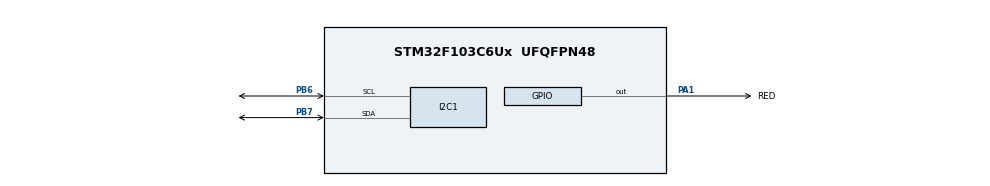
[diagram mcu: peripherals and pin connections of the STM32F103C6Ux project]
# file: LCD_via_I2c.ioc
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Mcu.Family=STM32F1
Mcu.Name=STM32F103C6Ux
Mcu.Package=UFQFPN48
NVIC.PriorityGroup=NVIC_PRIORITYGROUP_4
NVIC.TIM2_IRQn=true\:0\:0\:false\:false\:true\:true\:true\:true
PA1.GPIO_Label=RED
PA1.Signal=GPIO_Output
PA13.Mode=Serial_Wire
PA13.Signal=SYS_JTMS-SWDIO
PA14.Mode=Serial_Wire
PA14.Signal=SYS_JTCK-SWCLK
PB6.Mode=I2C
PB6.Signal=I2C1_SCL
PB7.Mode=I2C
PB7.Signal=I2C1_SDA
ProjectManager.HeapSize=0x200
ProjectManager.StackSize=0x400
ProjectManager.TargetToolchain=STM32CubeIDE
RCC.AHBFreq_Value=8000000
RCC.APB1CLKDivider=RCC_HCLK_DIV2
RCC.APB1Freq_Value=4000000
RCC.APB1TimFreq_Value=8000000
RCC.APB2Freq_Value=8000000
RCC.APB2TimFreq_Value=8000000
RCC.HCLKFreq_Value=8000000
RCC.PLLMUL=RCC_PLL_MUL9
RCC.SYSCLKFreq_VALUE=8000000
RCC.USBFreq_Value=36000000
TIM2.Period=9
TIM2.Prescaler=7999
VP_TIM2_VS_ClockSourceINT.Mode=Internal
board=custom

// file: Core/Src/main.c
/* USER CODE BEGIN Header */
/**
  ******************************************************************************
  * @file           : main.c
  * @brief          : Main program body
  ******************************************************************************
  * @attention
  *
  * Copyright (c) 2022 STMicroelectronics.
  * All rights reserved.
  *
  * This software is licensed under terms that can be found in the LICENSE file
  * in the root directory of this software component.
  * If no LICENSE file comes with this software, it is provided AS-IS.
  *
  ******************************************************************************
  */
/* USER CODE END Header */
#include "main.h"

/* USER CODE BEGIN Includes */
#include "software_timer.h"
#include "i2c-lcd-v2.h"
#include "liquidcrystal_i2c.h"
#include "CLCD_i2c.h"
#include "app_i2c_lcd.h"
/* USER CODE END Includes */

I2C_HandleTypeDef hi2c1;

TIM_HandleTypeDef htim2;

/* USER CODE BEGIN PV */
CLCD_I2C_Name LCD1;
/* USER CODE END PV */

void SystemClock_Config(void);
static void MX_GPIO_Init(void);
static void MX_I2C1_Init(void);
static void MX_TIM2_Init(void);

int main(void)
{

  /* MCU Configuration--------------------------------------------------------*/

  /* Reset of all peripherals, Initializes the Flash interface and the Systick. */
  HAL_Init();

  /* Configure the system clock */
  SystemClock_Config();

  /* Initialize all configured peripherals */
  MX_GPIO_Init();
  MX_I2C1_Init();
  MX_TIM2_Init();
  /* USER CODE BEGIN 2 */
  HAL_TIM_Base_Start_IT(&htim2);

  	  // CLCD_i2c
//  CLCD_I2C_Init(&LCD1, &hi2c1, 0x4E, 16, 2);
//  CLCD_I2C_SetCursor(&LCD1, 0, 0);
//  CLCD_I2C_WriteString(&LCD1, "Hello World");
//  CLCD_I2C_SetCursor(&LCD1, 0, 1);
//  CLCD_I2C_WriteString(&LCD1, "From BK");

  	  //i2c-lcd-v2
  HAL_Delay(1000);
  lcd_init();
  lcd_goto_XY(1,0);
  lcd_send_string("Hello World");
  HAL_Delay(50);
  lcd_goto_XY(2,0);
  lcd_send_string("From BK");

  	  // app_i2c_lcd
//  	HAL_Delay(1000);
//  	Lcd_Initialization();
//  	Lcd_Goto_XY(0,0);
//  	Lcd_Send_String("Hello World");
//  	HAL_Delay(50);
  /* USER CODE END 2 */

  /* Infinite loop */
  /* USER CODE BEGIN WHILE */
  setTimer1(100);
  while (1)
  {
    /* USER CODE END WHILE */

    /* USER CODE BEGIN 3 */
	  if (timer1_flag == 1){
		  HAL_GPIO_TogglePin(RED_GPIO_Port, RED_Pin);
		  setTimer1(100);
	  }
  }
  /* USER CODE END 3 */
}

void SystemClock_Config(void)
{
  RCC_OscInitTypeDef RCC_OscInitStruct = {0};
  RCC_ClkInitTypeDef RCC_ClkInitStruct = {0};

  /** Initializes the RCC Oscillators according to the specified parameters
  * in the RCC_OscInitTypeDef structure.
  */
  RCC_OscInitStruct.OscillatorType = RCC_OSCILLATORTYPE_HSI;
  RCC_OscInitStruct.HSIState = RCC_HSI_ON;
  RCC_OscInitStruct.HSICalibrationValue = RCC_HSICALIBRATION_DEFAULT;
  RCC_OscInitStruct.PLL.PLLState = RCC_PLL_NONE;
  if (HAL_RCC_OscConfig(&RCC_OscInitStruct) != HAL_OK)
  {
    Error_Handler();
  }

  /** Initializes the CPU, AHB and APB buses clocks
  */
  RCC_ClkInitStruct.ClockType = RCC_CLOCKTYPE_HCLK|RCC_CLOCKTYPE_SYSCLK
                              |RCC_CLOCKTYPE_PCLK1|RCC_CLOCKTYPE_PCLK2;
  RCC_ClkInitStruct.SYSCLKSource = RCC_SYSCLKSOURCE_HSI;
  RCC_ClkInitStruct.AHBCLKDivider = RCC_SYSCLK_DIV1;
  RCC_ClkInitStruct.APB1CLKDivider = RCC_HCLK_DIV1;
  RCC_ClkInitStruct.APB2CLKDivider = RCC_HCLK_DIV1;

  if (HAL_RCC_ClockConfig(&RCC_ClkInitStruct, FLASH_LATENCY_0) != HAL_OK)
  {
    Error_Handler();
  }
}

static void MX_I2C1_Init(void)
{

  hi2c1.Instance = I2C1;
  hi2c1.Init.ClockSpeed = 100000;
  hi2c1.Init.DutyCycle = I2C_DUTYCYCLE_2;
  hi2c1.Init.OwnAddress1 = 0;
  hi2c1.Init.AddressingMode = I2C_ADDRESSINGMODE_7BIT;
  hi2c1.Init.DualAddressMode = I2C_DUALADDRESS_DISABLE;
  hi2c1.Init.OwnAddress2 = 0;
  hi2c1.Init.GeneralCallMode = I2C_GENERALCALL_DISABLE;
  hi2c1.Init.NoStretchMode = I2C_NOSTRETCH_DISABLE;
  if (HAL_I2C_Init(&hi2c1) != HAL_OK)
  {
    Error_Handler();
  }

}

static void MX_TIM2_Init(void)
{

  TIM_ClockConfigTypeDef sClockSourceConfig = {0};
  TIM_MasterConfigTypeDef sMasterConfig = {0};

  htim2.Instance = TIM2;
  htim2.Init.Prescaler = 7999;
  htim2.Init.CounterMode = TIM_COUNTERMODE_UP;
  htim2.Init.Period = 9;
  htim2.Init.ClockDivision = TIM_CLOCKDIVISION_DIV1;
  htim2.Init.AutoReloadPreload = TIM_AUTORELOAD_PRELOAD_DISABLE;
  if (HAL_TIM_Base_Init(&htim2) != HAL_OK)
  {
    Error_Handler();
  }
  sClockSourceConfig.ClockSource = TIM_CLOCKSOURCE_INTERNAL;
  if (HAL_TIM_ConfigClockSource(&htim2, &sClockSourceConfig) != HAL_OK)
  {
    Error_Handler();
  }
  sMasterConfig.MasterOutputTrigger = TIM_TRGO_RESET;
  sMasterConfig.MasterSlaveMode = TIM_MASTERSLAVEMODE_DISABLE;
  if (HAL_TIMEx_MasterConfigSynchronization(&htim2, &sMasterConfig) != HAL_OK)
  {
    Error_Handler();
  }

}

static void MX_GPIO_Init(void)
{
  GPIO_InitTypeDef GPIO_InitStruct = {0};

  /* GPIO Ports Clock Enable */
  __HAL_RCC_GPIOA_CLK_ENABLE();
  __HAL_RCC_GPIOB_CLK_ENABLE();

  /*Configure GPIO pin Output Level */
  HAL_GPIO_WritePin(RED_GPIO_Port, RED_Pin, GPIO_PIN_RESET);

  /*Configure GPIO pin : RED_Pin */
  GPIO_InitStruct.Pin = RED_Pin;
  GPIO_InitStruct.Mode = GPIO_MODE_OUTPUT_PP;
  GPIO_InitStruct.Pull = GPIO_NOPULL;
  GPIO_InitStruct.Speed = GPIO_SPEED_FREQ_LOW;
  HAL_GPIO_Init(RED_GPIO_Port, &GPIO_InitStruct);

}

/* USER CODE BEGIN 4 */
void HAL_TIM_PeriodElapsedCallback ( TIM_HandleTypeDef * htim )
{
	timerRun();
}
/* USER CODE END 4 */

void Error_Handler(void)
{
  __disable_irq();
  while (1)
  {
  }
}
